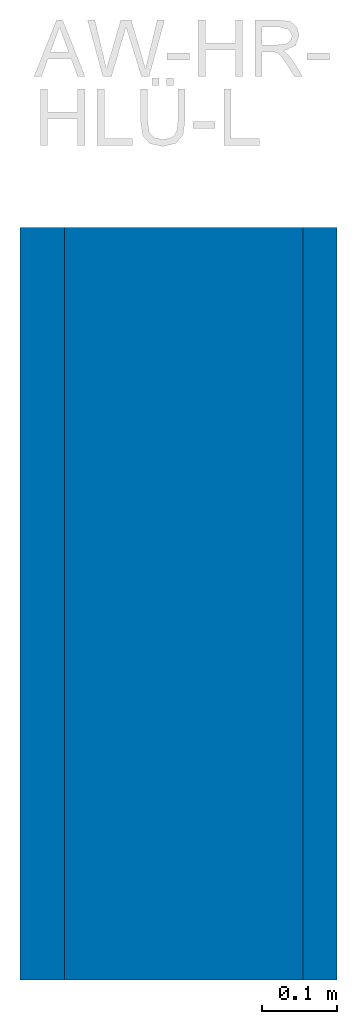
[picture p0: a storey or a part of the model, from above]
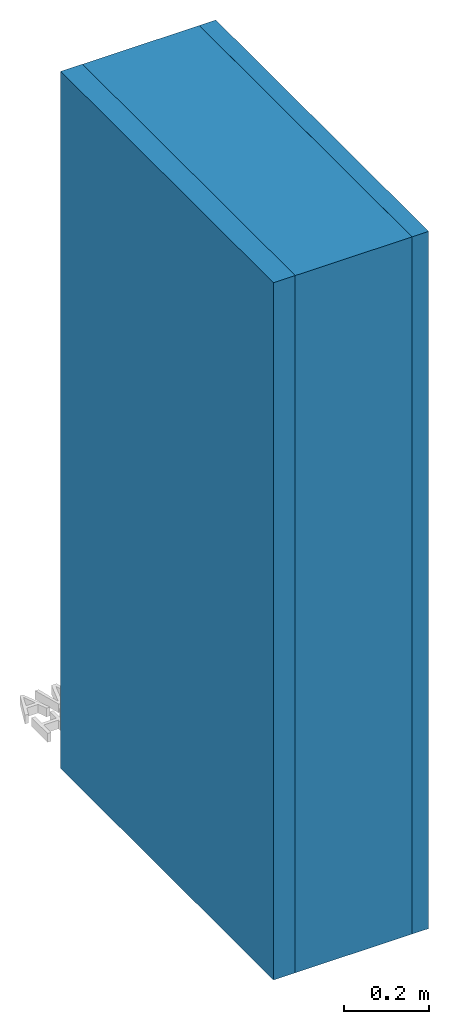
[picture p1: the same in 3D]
Properties of the parts of a building model (IFC4)

# File
Description: ViewDefinition [ReferenceView_V1.2], RevitIdentifiers [VersionGUID: 93d8a1e2-35a5-4253-ab7c-23872298a1db, NumberOfSaves: 0], CoordinateReference [CoordinateBase: Gemeinsam genutzte Koordinaten], ExchangeRequirement [Architecture]
File name: 2018_01
Time: 2023-06-27T14:37:18+01:00
Written by: ODA SDAI 23.12
Made in: Autodesk Revit 24.0.5.432 (DEU) - IFC 24.0.5.432

# IfcProject, 2018_01
Phase: Projekt Status

# IfcSite, Default
RefLatitude: 48, 8, 15, 359802; RefLongitude: 11, 34, 47, 783432; RefElevation: 0 m
Pset_SiteCommon - Reference: Projektinformationen

# IfcBuildingElementProxy: Modelltext:075mm Arial, Modelltext:075mm Arial:2509492
In: Default
Type - Pset_BuildingElementProxyCommon - IsExternal: no
Pset_BuildingElementProxyCommon - Reference: 075mm Arial
Pset_EnvironmentalImpactIndicators - Reference: 075mm Arial
Qto_BuildingElementProxyQuantities - NetSurfaceArea: 0.114041 m2; NetVolume: 0.000364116 m3

# IfcElementAssembly: Wände Baugruppe:fbimSg_Wall_bc_WOD_vis_at_NTR_natuREbuilt_AW-HR-HLÜ-L_GK3_42cm, Wände Baugruppe:fbimSg_Wall_bc_WOD_vis_at_NTR_natuREbuilt_AW-HR-HLÜ-L_GK3_42cm:2509496
In: Default
PredefinedType: USERDEFINED
Pset_ElementAssemblyCommon - Reference: fbimSg_Wall_bc_WOD_vis_at_NTR_natuREbuilt_AW-HR-HLÜ-L_GK3_42cm; sets with these values: 2

# IfcWall: Basiswand:fbimSg_Wall_dp_PLA_vis_at_NTR_natuREbuilt_AWRh-I_GK3_i_Lehm, Basiswand:fbimSg_Wall_dp_PLA_vis_at_NTR_natuREbuilt_AWRh-I_GK3_i_Lehm:2509495
In: Default
Type - PredefinedType: STANDARD; Material: fbim_16200505_at_NTR_Lehm_Grundputz, fbim_16200510_at_NTR_Lehm_Duennputz
Type - Pset_WallCommon - IsExternal: no
Qto_WallBaseQuantities - fbim_16200505_at_NTR_Lehm_Grundputz, Width: 0.04 m; fbim_16200510_at_NTR_Lehm_Duennputz, Width: 0.005 m; Width: 0.045 m; Height: 2 m; Length: 1 m; GrossVolume: 0.09 m3; GrossSideArea: 2 m2; NetSideArea: 2 m2; NetVolume: 0.09 m3
Pset_EnvironmentalImpactIndicators - Reference: fbimSg_Wall_dp_PLA_vis_at_NTR_natuREbuilt_AWRh-I_GK3_i_Lehm; sets with these values: 2
Pset_WallCommon - LoadBearing: no; ExtendToStructure: no; Reference: fbimSg_Wall_dp_PLA_vis_at_NTR_natuREbuilt_AWRh-I_GK3_i_Lehm

# IfcWall: Basiswand:fbimSg_Wall_dp_WOD_vis_at_NTR_natuREbuilt_AWRh-I_GK3_a_4cm, Basiswand:fbimSg_Wall_dp_WOD_vis_at_NTR_natuREbuilt_AWRh-I_GK3_a_4cm:2509493
In: Default
Type - PredefinedType: STANDARD; Material: fbim_12400515_AT_025_Vollholz_Bretter_Fichte, fbim_14100590_AT_001_Luftschicht
Type - Pset_WallCommon - IsExternal: no
Qto_WallBaseQuantities - fbim_12400515_AT_025_Vollholz_Bretter_Fichte, Width: 0.019 m; fbim_14100590_AT_001_Luftschicht, Width: 0.04 m; Width: 0.059 m; Height: 2 m; Length: 1 m; GrossVolume: 0.118 m3; GrossSideArea: 2 m2; NetSideArea: 2 m2; NetVolume: 0.118 m3
Pset_EnvironmentalImpactIndicators - Reference: fbimSg_Wall_dp_WOD_vis_at_NTR_natuREbuilt_AWRh-I_GK3_a_4cm; sets with these values: 2
Pset_WallCommon - Reference: fbimSg_Wall_dp_WOD_vis_at_NTR_natuREbuilt_AWRh-I_GK3_a_4cm; LoadBearing: no; ExtendToStructure: no

# IfcWall: Basiswand:fbimSg_Wall_sb_WOD_vis_at_NTR_natuREbuilt_AWRh-I_GK3_k_28cm, Basiswand:fbimSg_Wall_sb_WOD_vis_at_NTR_natuREbuilt_AWRh-I_GK3_k_28cm:2509494
In: Default
Type - PredefinedType: STANDARD; Material: fbim_12400515_AT_025_Vollholz_Bretter_Fichte, fbim_14100500_at_NTR_Zellulose-Einblasdaemmung, fbim_12401520_AT_OSB
Type - Pset_WallCommon - IsExternal: no
Qto_WallBaseQuantities - fbim_12400515_AT_025_Vollholz_Bretter_Fichte, Width: 0.022 m; fbim_14100500_at_NTR_Zellulose-Einblasdaemmung, Width: 0.28 m; fbim_12401520_AT_OSB, Width: 0.015 m; Width: 0.317 m; Height: 2 m; Length: 1 m; GrossVolume: 0.634 m3; GrossSideArea: 2 m2; NetSideArea: 2 m2; NetVolume: 0.634 m3
Pset_EnvironmentalImpactIndicators - Reference: fbimSg_Wall_sb_WOD_vis_at_NTR_natuREbuilt_AWRh-I_GK3_k_28cm; sets with these values: 2
Pset_WallCommon - LoadBearing: no; ExtendToStructure: no; Reference: fbimSg_Wall_sb_WOD_vis_at_NTR_natuREbuilt_AWRh-I_GK3_k_28cm
